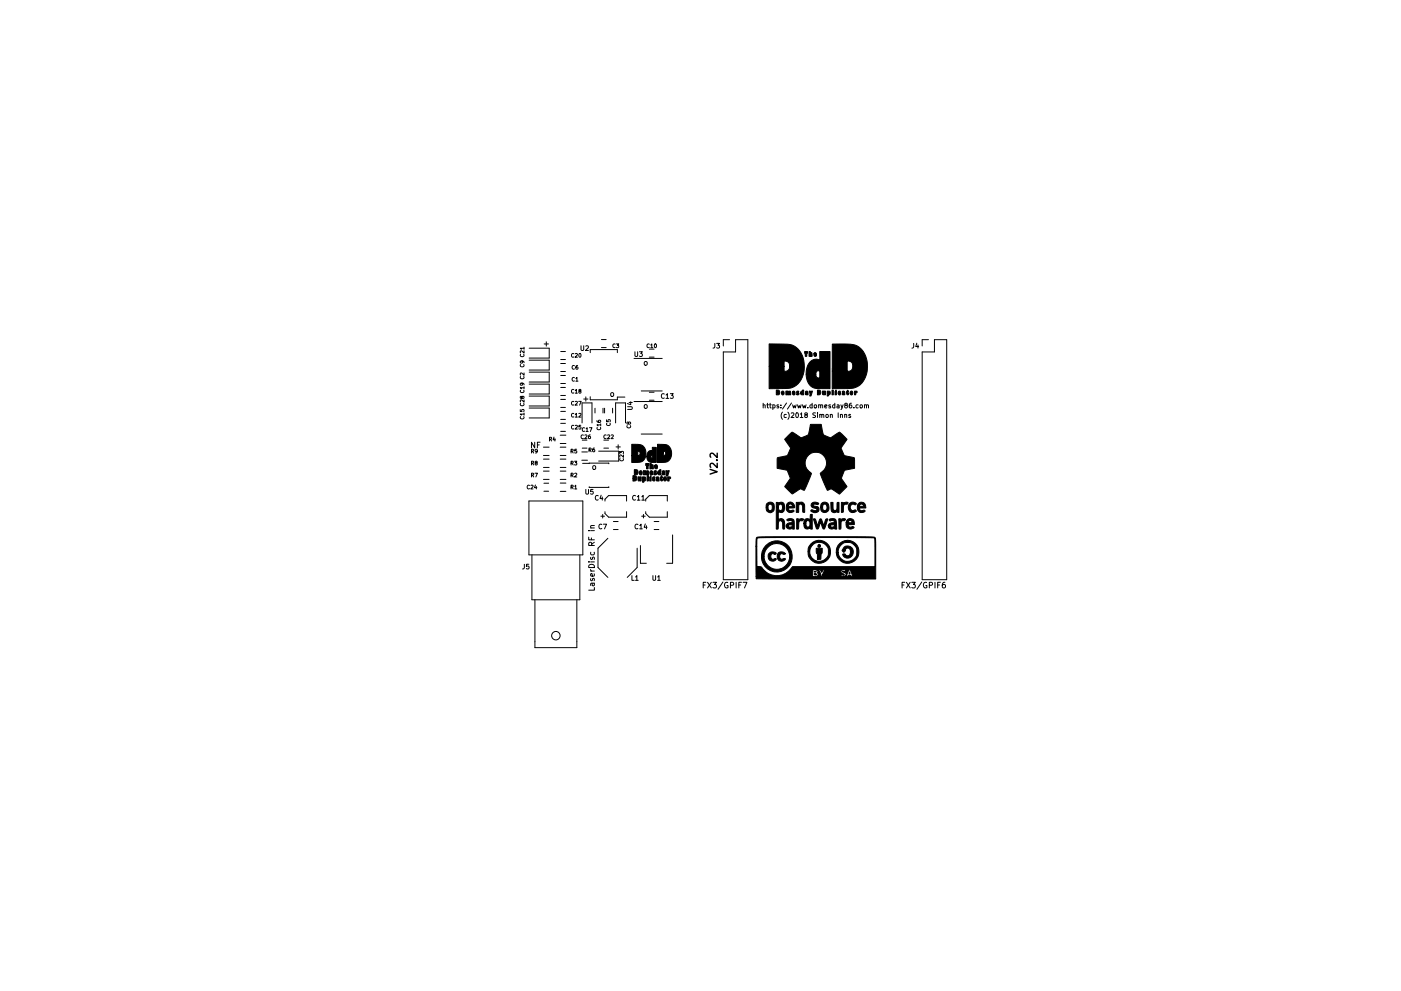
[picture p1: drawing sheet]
<svg xmlns="http://www.w3.org/2000/svg" width="297mm" height="210mm" viewBox="0 0 297 210" stroke-linecap="round" stroke-linejoin="round" font-family="sans-serif">
<path d="M150.6 99.6l1.5 .5-1.5 .5M151.9 97.6h.2M152.1 98.3v.9l-1.1-.9-.4 .3 .1 .5M152.1 96.1v1l-1.1-1-.4 .3 .1 .6" fill="none" stroke="#000" stroke-width=".3"/>
<g fill="none" stroke="#000" stroke-width=".21">
<path d="M110.4 79.9a.35 .35 0 0 0 .3 .5 .35 .35 0 0 0 .3-.5M110.4 77.3a.35 .35 0 0 0 .3 .5 .35 .35 0 0 0 .3-.5M110.4 75.2a.35 .35 0 0 0 .3 .5 .35 .35 0 0 0 .3-.5M110.6 76.6l.2 .4h-.4l-.1-.3 .2-.1h.4l.2 .4M111.1 79.1v.5l-.6-.5-.2 .2 .1 .3M111.1 74.4v.5l-.6-.5-.2 .2 .1 .3M111.1 73.9h-.8l.2 .2M111.1 73.7v.4M112.2 79h4.2v2.1h-4.2M112.2 73.9h4.2v2.1h-4.2M112.2 76.4h4.2v2.1h-4.2M115.4 73h.9"/>
<path d="M115.8 72.5v.9M118.9 79.7h1M118.9 78.8h1M118.9 77.1h1M118.9 76.3h1M118.9 74.6h1M121.7 75.1a.35 .35 0 0 0-.5 .3 .35 .35 0 0 0 .5 .3M121.8 77.6a.35 .35 0 0 0-.5 .3 .35 .35 0 0 0 .5 .4M122 75.1l.3-.1 .1 .2-.5 .6h.5M122.5 77.5l-.4 .2v.5l.1 .1h.3v-.4l-.4 .1M122.8 75h.1a.37 .37 0 0 1 .3 .4 .37 .37 0 0 1-.4 .3zM123.2 73.4v.8l.2 .2 .4-.2v-.8"/>
<path d="M124.2 73.5l.4-.1 .2 .2-.7 .8h.7M125.1 74.8v-.6h5.8v.6M127.5 72h1M127.5 73.7h1M130.4 73a.35 .35 0 0 0-.5 .4 .35 .35 0 0 0 .5 .3M130.7 73h.5l-.3 .3h.2v.4h-.4M134.4 76h6M134.6 74.6v.8l.2 .2 .4-.2v-.8M135.6 74.6h.6l-.3 .4 .2 .1v.4h-.5M136.6 76.8l.2-.1 .4 .1-.1 .6h-.5zM137.7 73a.35 .35 0 0 0-.5 .4 .35 .35 0 0 0 .5 .3M137.7 75.8h1"/>
<path d="M137.7 74.1h1M138 73.2l.2-.2v.8M138 73.8h.4M138.8 73h.1a.37 .37 0 0 1 .3 .4 .37 .37 0 0 1-.4 .3zM151.6 72.9l-.1 .8-.3 .2M151.9 72.9h.7l-.4 .3 .3 .1v.5h-.6M153.4 74.7h2.6v-2.6h2.6v50.9h-5.2zM154.7 72.1h-1.3v1.3M193.7 72.9v.8l-.4 .2M194.4 72.8l-.2 .7h.6M194.6 73.2v.7M195.5 74.7h2.6v-2.6h2.6v50.9h-5.2z"/>
<path d="M196.8 72.1h-1.3v1.3M110.3 86.9v.4h.4l-.1-.4h.4v.4M110.4 88.4a.35 .35 0 0 0 .3 .5 .35 .35 0 0 0 .3-.5M110.4 82.8a.35 .35 0 0 0 .3 .5 .35 .35 0 0 0 .3-.5M110.4 85.6a.35 .35 0 0 0 .3 .5 .35 .35 0 0 0 .3-.5M110.6 81.3l.2 .4h-.4l-.1-.3 .2-.1h.4l.2 .4M110.6 84.2l.4-.1v.4a.33 .33 0 0 1-.3-.1 .33 .33 0 0 1-.1-.3h-.2l-.1 .3 .2 .1 .1-.1M111.1 87.9h-.8l.2 .2M111.1 82.3h-.8l.2 .2M111.1 84.8v.5l-.6-.5-.2 .2 .1 .3M111.1 82v.5M111.1 87.6v.5"/>
<path d="M112.2 81.5h4.2v2.1h-4.2M112.2 84h4.2v2.1h-4.2M112.2 86.6h4.2v2.1h-4.2M112.7 98.3l.4-.1v-.3h-.4v.8M112.7 95.7h.4v-.3l-.4-.1v.8M112.9 98.3l.3 .4M112.9 95.7l.3 .4M113.4 93.8v1.2l-.7-1.2v1.2M113.6 98.2l-.1-.2 .1-.1h.3v.2a.32 .32 0 0 0-.4 .1 .32 .32 0 0 0 0 .4h.4l-.1-.4M113.9 95.7l-.4 .1v-.4l.3-.1 .1 .2v.4l-.4 .2M113.9 94.4h.4M114.5 93.8h-.6v1.2"/>
<path d="M115.2 100h1.2M115.2 99.2h1.2M115.2 97.4h1.2M115.2 96.6h1.2M115.2 94.9h1.2M116.5 93.2h.4v-.3l-.4-.1v.8M116.7 93.2l.3 .4M117.5 92.7l-.2 .6h.5M117.6 93v.6M118.8 100h1.2M118.8 99.2h1.2M118.8 97.4h1.2"/>
<path d="M118.8 92.3h1.2M118.8 94.1h1.2M118.8 96.6h1.2M118.8 94.9h1.2M118.9 81.4h1M118.9 89h1M118.9 87.3h1M118.9 83.9h1M118.9 82.2h1M118.9 91.5h1M118.9 89.8h1M118.9 86.4h1"/>
<path d="M118.9 84.7h1M121.1 98.3l.4-.1v-.3h-.4v.8M121.1 95.7h.4v-.3l-.4-.1v.8M121.3 98.3l.2 .4M121.3 95.7l.2 .4M121.7 87.8a.35 .35 0 0 0-.5 .3 .35 .35 0 0 0 .5 .3M121.7 82.7a.35 .35 0 0 0-.5 .3 .35 .35 0 0 0 .5 .3M121.7 90.3a.35 .35 0 0 0-.5 .3 .35 .35 0 0 0 .5 .4M121.7 85.2a.35 .35 0 0 0-.5 .4 .35 .35 0 0 0 .5 .3M121.8 80.2a.35 .35 0 0 0-.5 .3 .35 .35 0 0 0 .5 .3M121.8 97.9h.5l-.3 .3h.3v.4h-.5M122 87.9l.2-.2v.8"/>
<path d="M122 82.8l.2-.2v.8M122 90.3l.3-.1 .1 .3-.5 .5h.5M122 85.2h.3l.1 .2-.5 .6h.5M122 88.5h.4M122 83.4h.4M122.1 80.3l.2-.2v.8M122.1 80.9h.4M122.3 95.3h-.4l-.1 .4h.4l.1 .3h-.5M122.7 85.2h.5l-.3 .8M122.7 87.8l.3-.1 .2 .2-.5 .6h.5M122.9 83l-.2-.2 .2-.2 .2 .1v.2a.32 .32 0 0 0-.3 .1 .32 .32 0 0 0 0 .4l.3-.1-.1-.3M123.1 90.2h-.3l-.1 .4h.4v.4h-.4"/>
<path d="M123.4 95.9h1.2M123.4 97.6h1.2M123.4 89.7v-4.2h2.1v4.2M123.5 95.1h1M123.5 93.4h1M123.5 98.3h5.6v.1M123.7 92.3a.35 .35 0 0 0-.5 .4 .35 .35 0 0 0 .5 .3M123.7 84.7h1M123.9 90.8a.35 .35 0 0 0-.5 .3 .35 .35 0 0 0 .5 .4M124 92.3h.3l.2 .2-.5 .6h.5M124.2 84.2v.9M124.3 91l.2-.3v.8"/>
<path d="M124.3 91.5h.4M124.9 95.5l.4-.1v-.3h-.4v.8M125 90.7h.5l-.3 .8M125.1 95.5l.2 .4M125.1 92.3l-.3 .2v.4l.1 .2 .3-.1-.1-.4-.3 .1M125.1 84.2v.6h5.8v-.6h1.6M125.7 98.9l.2-.1 .3 .1v.6h-.5zM126 95.1l-.3 .2-.1 .4 .2 .2 .3-.1-.1-.4-.4 .1M126.2 86.6v1M126.6 89.2l.2 .4h.4l.2-.1-.1-.3h-.4l.1 .4M126.6 90.7a.35 .35 0 0 0 .4 .5 .35 .35 0 0 0 .3-.5M126.9 95.7h4.3v2.1h-4.3"/>
<path d="M127.4 90.1h-.8l.2 .3M127.4 89.9v.5M127.8 86.6v1M128 95.1h1M128 93.4h1M128.2 86.6v1M128.5 92.3a.35 .35 0 0 0-.5 .4 .35 .35 0 0 0 .5 .3M128.6 89.1v.3l.4 .1-.1-.4h.4v.4M128.7 89.8a.35 .35 0 0 0 .3 .5 .35 .35 0 0 0 .3-.5M128.8 92.3h.3l.2 .2-.5 .6h.5M129.5 83.4l.2-.1 .4 .1-.1 .6h-.5zM129.6 92.3h.3l.1 .2-.5 .6h.5"/>
<path d="M129.9 86.6v1M130.5 89.7v-4.2h2.1v4.2M130.6 94.8h.9M131.1 94.4v.9M131.4 96.3v-.5l.3 .2 .1-.2h.3v.5M131.5 97.3a.35 .35 0 0 0 .3 .5 .35 .35 0 0 0 .3-.5M132.2 96.5v.5l-.6-.5-.2 .2 .1 .3M133 90.3a.35 .35 0 0 0 .3 .5 .35 .35 0 0 0 .3-.5M133.1 86.3h.8l.2 .2-.2 .4h-.8M133.3 89.7l.3-.1v.4a.33 .33 0 0 1-.3-.1 .33 .33 0 0 1-.1-.3h-.2l-.1 .2 .2 .2 .2-.2M133.4 85.4h.7M133.7 85.2v.7l-.7-.3"/>
<path d="M134.4 85.2h6M136 82.9h4.4M136 92.1h4.4M136.6 86l.2-.2 .4 .2-.1 .6-.5-.1zM137.7 84.9h1M137.7 83.2h1M140.8 83.6a.44 .44 0 0 0-.6 .4 .44 .44 0 0 0 .6 .4M141.2 83.8l.3-.3v1M141.2 84.5h.6M142.1 83.5h.6l-.3 .4 .3 .1v.4h-.6M161.8 86l.4-.1v.7M161.8 85.6v1"/>
<path d="M162.6 85.9h.4M162.7 85.6v.8l.3 .2M163.1 85.9h.4M163.3 85.6v.8l.2 .2M163.9 85.9h.2l.2 .2-.1 .4h-.3M163.9 85.9v1M165.1 85.9l-.4 .1 .4 .3v.2h-.4M165.6 86.5v.1M165.6 85.9v.1M165.9 87.4a1.15 1.15 0 0 0 0 1.6M166.7 88l-.3-.1-.2 .2 .1 .4h.4M166.8 85.5l-.9 1.3"/>
<path d="M167 87.4a1.15 1.15 0 0 1 0 1.6M167.8 87.7l.3-.1 .2 .3-.6 .7h.6M167.8 85.5l-.8 1.3M168 85.9l.2 .7 .2-.5 .2 .5 .2-.7M168.9 87.6h.1a.49 .49 0 0 1 .3 .5 .49 .49 0 0 1-.4 .4l-.2-.3zM169.1 85.9l.2 .7 .2-.5 .2 .5 .2-.7M169.7 87.9l.3-.3v1M169.7 88.6h.5M170.1 85.9l.2 .7 .2-.5 .2 .5 .2-.7M170.8 88l-.1-.3 .4-.1v.3l-.5 .3 .2 .4 .4-.2-.2-.4M171.3 86.5v.1M172.2 85.9h-.3l-.2 .2 .1 .4h.4"/>
<path d="M172.2 85.6v1M172.7 86h.4l-.1 .5h-.3zM172.9 87.6l-.5 .1a.42 .42 0 0 0 .5 .5l-.1 .3h-.5M173.3 87.6v.1M173.3 87.9v.7M173.6 86l.4-.1v.7M173.6 85.9v.7M173.8 88h.4v.6M173.8 87.9v.7M174 86l.4-.1v.7M174.2 88.1l.4-.1 .1 .6M174.9 86.2l.4-.1v-.2h-.3l-.1 .1v.5h.4"/>
<path d="M175.1 88h.5l-.1 .5h-.4zM176 88h.4l.1 .6M176 87.9v.7M176.1 85.9l-.4 .1 .4 .3v.2h-.4M177 85.9h-.3l-.2 .2 .1 .4h.4M177 85.6v1M177.5 85.9h.4v.7M177.7 87.6v1M177.9 86.1l-.5 .2 .2 .3 .3-.1M178.2 88h.4v.6M178.2 87.9v.7M178.3 85.9l.2 .7"/>
<path d="M178.8 85.9l-.5 1M179.1 88h.4v.6M179.1 87.9v.7M179.3 86l-.2-.4h.5v.3l-.5 .3 .2 .4 .4-.2-.2-.4M180.3 88l-.3 .1 .3 .2v.2h-.3M180.5 85.6l-.4 .2-.1 .6 .2 .2 .4-.1-.1-.5-.3-.1-.2 .2M181 86.5v.1M182 85.9h-.3l-.2 .2 .1 .4h.4M182.4 85.9h.3l.2 .2v.3l-.2 .2-.4-.2zM183.3 86l.4-.1v.7M183.3 85.9v.7M183.7 86l.4-.1v.7"/>
<path d="M111.2 119.7l-.1 .9-.3 .1M112.1 119.7h-.5v.5l.5-.1v.5h-.5M112.1 106.3h11.5v11.4h-11.5zM112.3 103a.35 .35 0 0 0-.5 .3 .35 .35 0 0 0 .5 .4M112.6 103l.3-.1 .1 .3-.5 .5h.5M112.7 100.8h.4v-.3l-.4-.1v.8M112.8 117.7v9.5h10.1v-9.5M112.9 100.8l.3 .4M113.4 100.4h.6l-.4 .8M113.5 102.9l-.2 .6h.5M113.7 103.2v.5M115.2 101.7h1.2"/>
<path d="M115.3 104.2h1M115.3 102.5h1M118.8 102.5h1.2M118.8 104.3h1.2M118.8 101.7h1.2M121.1 103.4l.4-.1v-.3l-.4-.1v.8M121.1 100.8h.4v-.3l-.4-.1v.8M121.3 103.4l.2 .3M121.3 100.8l.2 .4M121.8 103.2l.3-.3v.8M121.8 100.5l.3-.1 .2 .2-.5 .6h.5M121.8 103.7h.5"/>
<path d="M124.2 103.8v.9l.2 .1 .4-.1v-.9M124.8 119.2h.1M124.8 114v.5h1.2M124.8 112.6h.1M124.9 120a.64 .64 0 0 1 .7-.2 .64 .64 0 0 1 .4 .6h-1.2zM124.9 103.3v.1h4.2v-.1M125.2 119.2h.8M125.2 112.6h.8M125.2 112h.8M125.3 118.2l-.1 .3 .2 .2 .2-.1 .1-.4h.3v.5M125.3 117.2l-.1 .3 .2 .2 .6-.1v-.4M125.4 114.1v.4"/>
<path d="M125.4 115.7v-.5l-.5-.1-.1 .6h1.2M125.7 103.8h-.4l-.1 .5h.5v.4h-.5M126 111.5l-.7 .1v.4M126 115l-.6 .4M126.8 105.2a.44 .44 0 0 0-.6 .4 .44 .44 0 0 0 .6 .4M127.4 109.5h.8M127.5 105.1l-.3 .7h.6M127.6 111.3a.44 .44 0 0 0-.6 .4 .44 .44 0 0 0 .6 .4M127.7 105.4v.7M127.8 109.1v.8M127.9 111.2h.7l-.4 1M128.3 106.3v-.4l.7-.8h3.8v1.2"/>
<path d="M128.3 108.6v.4l.7 .7h3.8v-1.1M128.9 114.2l-2.1 2.1v4.1l2.1 2.1M130.1 110.7h1M130.1 112.4h1M134.7 105.2a.44 .44 0 0 0-.6 .4 .44 .44 0 0 0 .6 .4M135.1 116.3v4.1l-2.1 2.1M135.1 105.4l.3-.3v1M135.1 106.1h.6M135.2 111.3a.44 .44 0 0 0-.6 .4 .44 .44 0 0 0 .6 .4M135.6 111.5l.3-.3v1M135.6 112.2h.6M135.8 115.7v3.8h1.2"/>
<path d="M136 109.5h.8M136.1 105.4l.3-.3v1M136.1 106.1h.5M136.4 109.1v.8M136.8 111.2l-.2 .7h.6M136.9 108.6v.4l.8 .7h3.8v-1.1M136.9 106.3v-.4l.8-.8h3.8v1.2M137.1 111.5v.7M138.7 110.7h1M138.7 112.4h1M142.6 113.5v6h-1.3M113.4 127.2v10.2h8.9v-10.2"/>
<path d="M125.2 120.8l.2 .4M125.2 121.2h.8M125.3 122.8l-.1 .2 .2 .2h.2l.1-.4h.3v.4M125.5 123.7l.2 .6 .3-.2v-.4M126 121.7v.4l-.2 .1h-.5v-.5h.2l.1 .5M126 124.6v.6h-1.2M126 123.7l-.7 .1v.4M134 122.1v1h.5M134.7 122.4l.3-.3v1M134.7 123.1h.6M138.4 122.1v.8l.2 .2 .4-.2v-.8M139.4 122.4l.3-.3v1"/>
<path d="M139.4 123.1h.6M149.1 124.1h.4M149.7 123.5h-.6v1.2M150 123.5l.8 1.2M150.8 123.5l-.8 1.2M151.2 123.5h.7l-.4 .5 .3 .1v.5l-.1 .1-.5-.1M153.3 123.5l-1.1 1.5M154.3 123.6a.55 .55 0 0 0-.7 .6 .55 .55 0 0 0 .8 .4v-.4h-.3M154.9 124.2l.5-.1 .1-.4-.6-.2v1.2M156.1 123.5v1.2M156.6 124.1h.4M157.2 123.5h-.6v1.2"/>
<path d="M157.6 123.5h.8l-.6 1.2M191.3 124.1h.4M191.8 123.5h-.5v1.2M192.2 123.5l.8 1.2M193 123.5l-.8 1.2M193.3 123.5h.8l-.4 .5 .3 .1v.5l-.2 .1-.5-.1M195.4 123.5l-1 1.5M196.5 123.6a.55 .55 0 0 0-.7 .6 .55 .55 0 0 0 .7 .4v-.4h-.2M197 124.2l.6-.1 .1-.4-.7-.2v1.2M198.2 123.5v1.2M198.8 124.1h.4M199.4 123.5h-.6v1.2"/>
<path d="M200.3 123.5l-.3 .1-.2 .2v.7l.2 .2 .4-.1-.1-.5-.3-.1-.2 .2"/>
<circle cx="117.9" cy="134.9" r=".9"/>
</g>
<g fill="#000" stroke="#000" stroke-width=".21">
<path d="M163.1 73h2.5a4 4 0 0 1 4.7 2.9 5.2 5.2 0 0 1-2.2 6.3l-1.1 .2-3.9 .1v-4.8h3.1v1.1a1.06 1.06 0 0 0 1.3-1.1 1.06 1.06 0 0 0-1.2-1l-.1 1h-3.1zM170.6 74.6h.6l-.2 1h-.3zM171.5 74.6h.3v.3h.3l.1 .7h-.3v-.5l-.1 .5h-.3zM172.7 74.9a.25 .25 0 0 1 .3 0 .25 .25 0 0 1-.1 .4h-.1l.3 .1v.1h-.5v-.5l.3 .1-.3-.1zM173.8 74.6h2.2v7.9h-1.7a2.72 2.72 0 0 1-3.4-3.1h2.1l.1 .6 .6 .2h.1v-.7a.55 .55 0 0 0-.3-.9l-.3 .2-.2 .6h-2.1a2.83 2.83 0 0 1 2-3.2l.9 .2zM176.5 73h2.7a4.1 4.1 0 0 1 4.7 4.3 4.3 4.3 0 0 1-3.4 5.1l-4.1 .1 .1-3.7h3.1a1.11 1.11 0 0 0 1.2-1.1 1.11 1.11 0 0 0-1.2-1.1v2.2h-3.1zM133.9 94.3a2.99 2.99 0 0 1 2.5 .4 2.01 2.01 0 0 1-.9 3.4h-1.6v-1.4h1.3a.42 .42 0 0 0 .5-.4 .42 .42 0 0 0-.5-.5v.9h-1.3zM134.5 99.6a.59 .59 0 0 1 .8 .6 .59 .59 0 0 1-.8 .5v-.5l.4 .1 .1-.1-.1-.1-.4 .1zM135.6 100a.4 .4 0 0 1 .6 .3 .4 .4 0 0 1-.5 .4l-.2-.4 .3 .1 .1-.1h-.4zM136.4 99.9l.7 .1 .3-.1 .1 .8h-.3v-.6l-.1 .6h-.3v-.6l-.1 .6h-.3zM136.9 98.3h.7l-.2 1.2h-.3zM137.8 98.3l.3 .1v.3h.4v.8h-.2l-.1-.7-.1 .7h-.3z"/>
<path d="M137.9 100l.3-.1 .2 .5h-.3l.3 .1a.36 .36 0 0 1-.5 .2 .36 .36 0 0 1-.1-.5h.4v-.1l-.4 .1zM138.3 94.9h.9v3.2h-1.1a1.07 1.07 0 0 1-1-1.2h.9l.1 .3h.2l-.1-.6-.2 .3h-.9a.95 .95 0 0 1 1.2-1.2zM138.8 99.9h.4l-.1 .2h-.2a.32 .32 0 0 1 .4 .3 .32 .32 0 0 1-.3 .3 .32 .32 0 0 1-.4-.2l.3 .1-.3-.5zM138.9 98.6a.28 .28 0 0 1 .4 .1 .28 .28 0 0 1 0 .4h-.2l.3 .1a.33 .33 0 0 1-.5 .2 .33 .33 0 0 1-.1-.4v-.1h.4h-.4zM139.4 94.3h.9a1.93 1.93 0 0 1 2.1 1.6 1.93 1.93 0 0 1-1.5 2.2h-1.5v-2h1.2v.4a.38 .38 0 0 0 .5-.3 .38 .38 0 0 0-.5-.4v.3h-1.2zM140.4 100a.36 .36 0 0 1 .5-.1 .36 .36 0 0 1 .1 .5v.3h-.6v-.2h.3h-.3l.3-.2-.3-.1zM141.1 99.9l.4 .2 .1-.2h.3l-.3 1.1h-.4l.1-.4zM164.6 82.8a.54 .54 0 0 1 .7 .5 .54 .54 0 0 1-.7 .5v-.5l.3 .1 .1-.1-.1-.2-.3 .2zM165.8 83a.36 .36 0 0 1 .4 .4 .36 .36 0 0 1-.4 .3l-.1-.3h.3h-.3zM166.6 83h.9l.1 .8h-.2l-.1-.6v.6h-.3l-.1-.6v.6h-.3zM168.1 83l.4 .1v.3l-.2 .1 .3 .1a.33 .33 0 0 1-.5 .1 .33 .33 0 0 1-.1-.5l.4 .1-.4-.1zM169 83h.3l-.1 .3a.27 .27 0 0 1 .2 .2 .27 .27 0 0 1-.3 .3l-.2-.1v-.2l.2 .1-.2-.4z"/>
<path d="M169.8 83.1l.6-.3v1l-.6-.2-.1-.2h.4v-.1l-.1 .1h-.3zM170.8 83a.34 .34 0 0 1 .5 .1 .34 .34 0 0 1 0 .4v.3l-.5-.1v-.1h.2h-.2l.2-.3-.2-.1zM171.6 83h.2l.1 .2 .1-.2h.3l-.1 .2a.78 .78 0 0 1-.4 .8h-.1v-.4zM173.3 82.8a.54 .54 0 0 1 .7 .5 .54 .54 0 0 1-.7 .5v-.5l.4 .1v-.1v-.2l-.4 .2zM167.1 92.4l.9-.7 1.8 1.2 1.4-.5 .2-.3 .4-2.1h2.3l.3 1.5a1.02 1.02 0 0 0 1 1.1l.7 .3 1.9-1.2 .8 .7 .8 .8-1.3 1.9 .3 .7a1.02 1.02 0 0 0 1.3 1.1l1.2 .2 .1 2.3-2.2 .4-.6 1.7 1.2 1.7-1.6 1.6-1.2-.7a.97 .97 0 0 0-1.4-.1l-1.5-3.5a2.41 2.41 0 0 0 1.3-2.4 2.41 2.41 0 0 0-1.6-2.1 2.35 2.35 0 0 0-2.8 1.5 2.35 2.35 0 0 0 1.2 2.9l-1.5 3.6a1.04 1.04 0 0 0-1.4 .1l-1.1 .7-1.6-1.6 1.2-1.7-.7-1.7-2.1-.4v-2.2l1.2-.3a1.02 1.02 0 0 0 1.3-1.1l.3-.7-1.2-1.9zM174.4 83h.2l.1 .5 .1-.5h.2v.8l-.6-.1zM175.4 83a.45 .45 0 0 1 .6 .1 .45 .45 0 0 1-.2 .7l-.4 .2v-.6h.3v.1l.1-.1h-.4zM176.4 82.8h.3v1h-.3zM177 83h.3v.8h-.3zM177.8 83h.4v.3l-.3 .1 .3 .1a.27 .27 0 0 1-.4 .2 .27 .27 0 0 1-.1-.4zM178.6 83.1a.33 .33 0 0 1 .4-.1 .33 .33 0 0 1 .1 .5v.3l-.5-.1v-.1h.2h-.2l.2-.3-.2-.1zM179.7 82.8l.2 .3v.6a.5 .5 0 0 1-.4-.4 .5 .5 0 0 1 .2-.5z"/>
<path d="M180.3 83.1a.35 .35 0 0 1 .5 .3 .35 .35 0 0 1-.4 .3l-.2-.3h.4h-.4zM181.2 83h.5v.3a.33 .33 0 0 0-.3 .5h-.2zM134.2 100.9a.59 .59 0 0 1 .8 .4 .59 .59 0 0 1-.4 .7l-.4 .1v-.6h.3l.1 .1 .1-.1-.1-.2-.1 .2h-.3zM135.3 101.2h.2l.1 .6v-.6h.4l-.1 .8h-.6zM136.2 101.2h.3a.45 .45 0 0 1 .4 .4 .45 .45 0 0 1-.4 .5v.2h-.3v-.7l.4 .2v-.2v-.1l-.4 .1zM137.2 100.9h.3v1.1h-.3zM137.9 100.9l.1 .2zM137.8 101.2h.2v.9h-.2zM138.4 101.3l.4-.1a.25 .25 0 0 1 .1 .3 .25 .25 0 0 1-.3 .1l.2 .3a.3 .3 0 0 1-.3 .1 .3 .3 0 0 1-.2-.4zM139.1 101.3a.36 .36 0 0 1 .5-.1 .36 .36 0 0 1 .1 .4v.5l-.5-.1-.1-.2h.3h-.3l.3-.3h-.3zM139.6 99.9l.5-.3v1.1h-.6l-.1-.3 .4 .1v-.2v-.1l-.1 .2h-.3zM140.3 100.9l.1 1.1a.32 .32 0 0 1-.4-.1 .32 .32 0 0 1 0-.4v-.2z"/>
<path d="M140.8 101.3l.1-.1a.41 .41 0 0 1 .4 .4 .41 .41 0 0 1-.5 .4l-.1-.4h.4l-.1-.1-.3 .1zM141.6 101.2l.6 .1a.21 .21 0 0 1-.1 .2 .21 .21 0 0 1-.2 .1v.5h-.3zM162.6 106.8a.91 .91 0 0 1 1.2-.2 .91 .91 0 0 1 .4 1.1 .89 .89 0 0 1-1 1.1 .89 .89 0 0 1-.8-1.2h.4a.57 .57 0 0 0 .6 .7 .74 .74 0 0 0 .3-.7 .74 .74 0 0 0-.6-.6l-.3 .6h-.4zM163 117.4a1.06 1.06 0 0 1 1.6 0l-.4 .2-.3-.2a.6 .6 0 0 0-.5 .9 .6 .6 0 0 0 .9 .2l.3 .1a.97 .97 0 0 1-1.4 .3 .97 .97 0 0 1-.2-1.5zM162.4 115.7a3.3 3.3 0 0 1 5.2 .6 3.3 3.3 0 0 1-1.9 4.9 3.3 3.3 0 0 1-4.2-3.1h.5a2.72 2.72 0 0 0 3.9 2.4 2.72 2.72 0 0 0 .5-4.6 2.72 2.72 0 0 0-4.4 1.6v.6h-.5a3.1 3.1 0 0 1 .9-2.4zM165 117.3a1.14 1.14 0 0 1 1.6 .2l-.4 .1a.56 .56 0 0 0-.8 .1 .56 .56 0 0 0 0 .7 .56 .56 0 0 0 .8 .1h.3a.99 .99 0 0 1-1.5 .3 .99 .99 0 0 1 0-1.5zM164.6 106.6l.4 .1a.88 .88 0 0 1 1 0 .88 .88 0 0 1 .3 .9 .81 .81 0 0 1-.3 1 .81 .81 0 0 1-1-.1v1.7a.84 .84 0 0 1 1 0 .84 .84 0 0 1 .4 .9l-.1 1.1h-.3l-.1-.3a1.07 1.07 0 0 0-.5-1.4 1.32 1.32 0 0 0-.4 1.4v.3l-.4 .1v-4.7h.4l.2 .6a.39 .39 0 0 0 .6-.1l.1-.9-.4-.3a.59 .59 0 0 0-.5 .7h-.4zM166.8 110.3a.98 .98 0 0 1 1.2-.1 .98 .98 0 0 1 .4 1.1v1l-.4-.1a.87 .87 0 0 1-1.3-.6l.9 .2 .3-.1 .1-.1-.1-.2h-.6l-.2 .2h-.4v-.2a1.38 1.38 0 0 1 1.3-.6 .48 .48 0 0 0-.4-.4 .48 .48 0 0 0-.5 .1zM167 106.8a.92 .92 0 0 1 1.1-.1 .92 .92 0 0 1 .3 1l-1.2 .1a.54 .54 0 0 0 .3 .6 .54 .54 0 0 0 .6-.2l.3 .2a1 1 0 0 1-1.4 .2 1 1 0 0 1-.3-1.3l1.3 .1a.45 .45 0 0 0-.4-.5 .45 .45 0 0 0-.5 .4h-.4zM168.9 110.1l1.5 .1a.51 .51 0 0 1-.7 .3 1.3 1.3 0 0 0-.4 1.4v.3l-.4 .1zM168.8 106.6a1.58 1.58 0 0 1 1.7 .4l.1 1.7h-.4v-1.1a.44 .44 0 0 0-.3-.6 .44 .44 0 0 0-.6 .4v1.3h-.5zM170.6 110.3a1 1 0 0 1 1.2-.1 .94 .94 0 0 1 .2-1.1h.2v3.2l-.4-.1v-.1a.86 .86 0 0 1-1.1 0 .86 .86 0 0 1-.3-1h.5a.56 .56 0 0 0 .6 .7 .77 .77 0 0 0 .3-.8 .77 .77 0 0 0-.6-.6l-.3 .7h-.5z"/>
<path d="M172.5 110.1a.97 .97 0 0 1 .7 1.1l.1 .3 .5-1.3 .3-.1 .5 1.3h.1a1.63 1.63 0 0 1 .6-1.3l.2 .1a3.5 3.5 0 0 1-.8 2.1l-.2-.2-.5-1.3-.5 1.3-.3 .1zM172.2 106.7a.99 .99 0 0 1 1.4 .2l-.2 .2-.8-.1-.2 .2 .3 .2a.73 .73 0 0 1 1 .8 .73 .73 0 0 1-1.1 .5l-.5-.2-.2-.2 .2-.2 .9 .2 .2-.2-.3-.3a.84 .84 0 0 1-.9-.6zM171.9 115.4a2.43 2.43 0 0 1 3.9 .3 2.43 2.43 0 0 1-1.2 3.6 2.43 2.43 0 0 1-3.3-2v-.3h.4a1.99 1.99 0 0 0 2.7 1.9 1.99 1.99 0 0 0 .6-3.2 1.99 1.99 0 0 0-3.2 .7l-.1 .6h-.4l.1-.8zM173.1 116.3h1.2l-.3 2.4h-.7zM160.4 114l2.6-.1h16.9h4.8l.8 .2 .2 8.7h-25h-.4v-.5h12.4l.6-.1a.49 .49 0 0 0 0-.7l.2-.3-.4-.3h.5l.6 1.4 .2-.3h3.8l.5 .3h.9a.61 .61 0 0 1 .5-.3 .61 .61 0 0 1 .6 .3l.1-.1-.3-.7-.4-.6-.7 1.4h-.5a.45 .45 0 0 0 .5-.5 .45 .45 0 0 0-.5-.4l-.3-.2 .6 .1a.46 .46 0 0 0-.5-.5 .46 .46 0 0 0-.3 .7l.5 .3 .1 .2-.7-.2-.1 .2h-3.8l.5-1.1h-.4l-.3 .5-.5-.6h-1.1l-.3 .2v1.3h-12v-6.4h.2v4.3l.9 .1a3.8 3.8 0 0 0 6.6-.1h17.5v-4.4a2.21 2.21 0 0 0-.2-1.7h-24.1a.51 .51 0 0 0-.6 0 .51 .51 0 0 0-.1 .6v1.2h-.2zM174.1 106.9a.94 .94 0 0 1 1.2-.3 .94 .94 0 0 1 .5 1.1 .9 .9 0 0 1-1 1.1 .9 .9 0 0 1-.8-1.2h.4l.1 .5 .3 .3a.71 .71 0 0 0 .5-.8 .71 .71 0 0 0-.5-.6l-.3 .2-.1 .4h-.4zM176.1 106.6h.5v1.1a.46 .46 0 0 0 .5 .6 .46 .46 0 0 0 .4-.6v-1.1h.4v2.1l-.4-.1a.83 .83 0 0 1-1 0 .83 .83 0 0 1-.3-.9zM175.9 110.2a.99 .99 0 0 1 1.1 0 .99 .99 0 0 1 .4 1.1v1l-.5-.1a.85 .85 0 0 1-1.3-.7h.4a.45 .45 0 0 0 .5 .3 .45 .45 0 0 0 .4-.4l-1.3 .1a1.6 1.6 0 0 1 1.4-.7 .58 .58 0 0 0-1-.2l-.2-.3zM177.8 110.1l.6 .1 .7-.1 .2 .1-.3 .3a.52 .52 0 0 0-.5 0 .52 .52 0 0 0-.2 .6v1.1l-.4 .1zM178.4 106.6h1.4l-.2 .4a.7 .7 0 0 0-.7 .2 .7 .7 0 0 0-.1 .8v.7h-.4zM179 116.1a1.24 1.24 0 0 1 1.7 .2 1.24 1.24 0 0 1-.2 1.7 1.24 1.24 0 0 1-1.7-.1l-.1-.3 .5-.1a.57 .57 0 0 0 .5 .4 .57 .57 0 0 0 .5-.3l.1-.3a.87 .87 0 0 0-.4-1 .49 .49 0 0 0-.7 .5l-.3 .4-.3-.3zM178.1 115.3a2.42 2.42 0 0 1 3.7 .5 2.42 2.42 0 0 1-1.3 3.5 2.42 2.42 0 0 1-3.2-2.1h.4a2 2 0 0 0 3 1.6 2 2 0 0 0 .2-3.3 2 2 0 0 0-3.2 1.2v.5h-.4a2.28 2.28 0 0 1 .8-1.9z"/>
<path d="M179.7 110.2a.94 .94 0 0 1 1.1 0 .94 .94 0 0 1 .3 1.1l-1.3 .1a.56 .56 0 0 0 .4 .5 .56 .56 0 0 0 .6-.2l.3 .2a.99 .99 0 0 1-1.3 .2 .99 .99 0 0 1-.4-1.3l.8 .1 .5-.1a.43 .43 0 0 0-.6-.3l-.3 .3h-.4zM180.2 106.8a.88 .88 0 0 1 1.4 .1l-.2 .2a.68 .68 0 0 0-1 .1 .68 .68 0 0 0 .1 1 .68 .68 0 0 0 .9 0l.2 .2a1.03 1.03 0 0 1-1.4 .2 1.03 1.03 0 0 1-.3-1.4zM182 106.8a.94 .94 0 0 1 1.2-.1 .94 .94 0 0 1 .4 1.1h-1.4a.54 .54 0 0 0 .4 .6 .54 .54 0 0 0 .6-.2l.2 .2a.99 .99 0 0 1-1.3 .2 .99 .99 0 0 1-.3-1.3l1.3 .1a.45 .45 0 0 0-.4-.5 .45 .45 0 0 0-.5 .4h-.4zM172.7 121.7h.4v.3h-.4zM172.7 121.2l.4 .1-.4 .1zM180.1 121.3v.4l-.1-.1z"/>
<circle cx="177.2" cy="82.9" r=".09"/>
<circle cx="173.7" cy="115.8" r=".31"/>
</g>
</svg>
